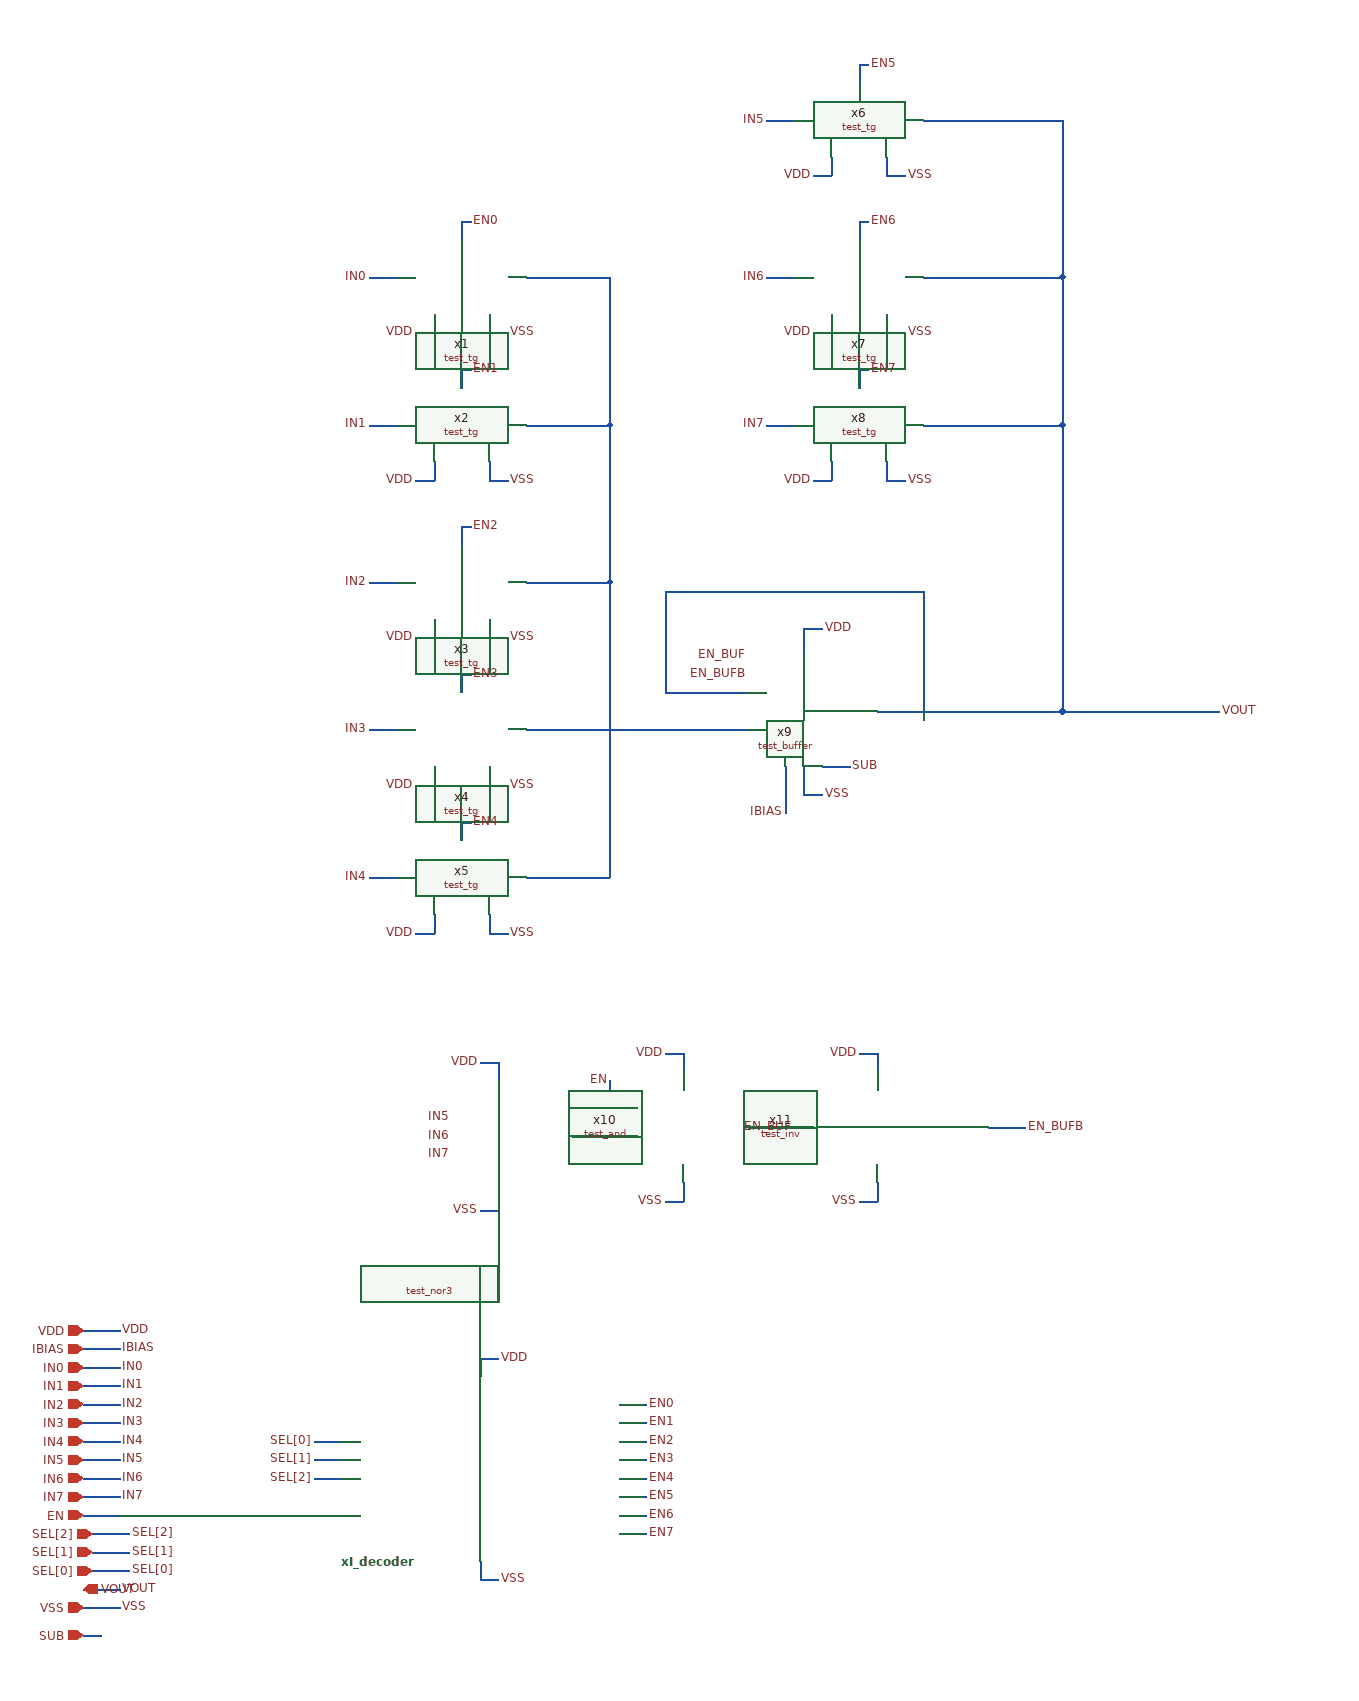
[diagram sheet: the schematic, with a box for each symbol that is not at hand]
v {xschem version=3.4.7 file_version=1.2}
G {}
K {}
V {}
S {}
E {}
N 150 -230 170 -230 {lab=SUB}
N 150 -520 190 -520 {lab=IN0}
N 150 -500 190 -500 {lab=IN1}
N 150 -480 190 -480 {lab=IN2}
N 150 -460 190 -460 {lab=IN3}
N 150 -440 190 -440 {lab=IN4}
N 150 -420 190 -420 {lab=IN5}
N 150 -400 190 -400 {lab=IN6}
N 150 -380 190 -380 {lab=IN7}
N 150 -360 190 -360 {lab=EN}
N 150 -540 190 -540 {lab=IBIAS}
N 150 -560 190 -560 {lab=VDD}
N 160 -340 200 -340 {lab=SEL[2]}
N 150 -280 190 -280 {lab=VOUT}
N 150 -260 190 -260 {lab=VSS}
N 460 -1700 490 -1700 {lab=IN0}
N 560 -1760 560 -1740 {lab=EN0}
N 560 -1760 570 -1760 {lab=EN0}
N 530 -1660 530 -1640 {lab=VDD}
N 510 -1640 530 -1640 {lab=VDD}
N 590 -1660 590 -1640 {lab=VSS}
N 590 -1640 610 -1640 {lab=VSS}
N 460 -1540 490 -1540 {lab=IN1}
N 560 -1600 560 -1580 {lab=EN1}
N 560 -1600 570 -1600 {lab=EN1}
N 530 -1500 530 -1480 {lab=VDD}
N 510 -1480 530 -1480 {lab=VDD}
N 590 -1500 590 -1480 {lab=VSS}
N 590 -1480 610 -1480 {lab=VSS}
N 460 -1370 490 -1370 {lab=IN2}
N 560 -1430 560 -1410 {lab=EN2}
N 560 -1430 570 -1430 {lab=EN2}
N 530 -1330 530 -1310 {lab=VDD}
N 510 -1310 530 -1310 {lab=VDD}
N 590 -1330 590 -1310 {lab=VSS}
N 590 -1310 610 -1310 {lab=VSS}
N 460 -1210 490 -1210 {lab=IN3}
N 560 -1270 560 -1250 {lab=EN3}
N 560 -1270 570 -1270 {lab=EN3}
N 530 -1170 530 -1150 {lab=VDD}
N 510 -1150 530 -1150 {lab=VDD}
N 590 -1170 590 -1150 {lab=VSS}
N 590 -1150 610 -1150 {lab=VSS}
N 460 -1050 490 -1050 {lab=IN4}
N 560 -1110 560 -1090 {lab=EN4}
N 560 -1110 570 -1110 {lab=EN4}
N 530 -1010 530 -990 {lab=VDD}
N 510 -990 530 -990 {lab=VDD}
N 590 -1010 590 -990 {lab=VSS}
N 590 -990 610 -990 {lab=VSS}
N 890 -1870 920 -1870 {lab=IN5}
N 990 -1930 990 -1910 {lab=EN5}
N 990 -1930 1000 -1930 {lab=EN5}
N 960 -1830 960 -1810 {lab=VDD}
N 940 -1810 960 -1810 {lab=VDD}
N 1020 -1830 1020 -1810 {lab=VSS}
N 1020 -1810 1040 -1810 {lab=VSS}
N 890 -1700 920 -1700 {lab=IN6}
N 990 -1760 990 -1740 {lab=EN6}
N 990 -1760 1000 -1760 {lab=EN6}
N 960 -1660 960 -1640 {lab=VDD}
N 940 -1640 960 -1640 {lab=VDD}
N 1020 -1660 1020 -1640 {lab=VSS}
N 1020 -1640 1040 -1640 {lab=VSS}
N 890 -1540 920 -1540 {lab=IN7}
N 990 -1600 990 -1580 {lab=EN7}
N 990 -1600 1000 -1600 {lab=EN7}
N 960 -1500 960 -1480 {lab=VDD}
N 940 -1480 960 -1480 {lab=VDD}
N 1020 -1500 1020 -1480 {lab=VSS}
N 1020 -1480 1040 -1480 {lab=VSS}
N 630 -1210 870 -1210 {lab=#net1}
N 630 -1370 720 -1370 {lab=#net1}
N 720 -1370 720 -1210 {lab=#net1}
N 630 -1540 720 -1540 {lab=#net1}
N 720 -1540 720 -1370 {lab=#net1}
N 630 -1700 720 -1700 {lab=#net1}
N 720 -1700 720 -1540 {lab=#net1}
N 630 -1050 720 -1050 {lab=#net1}
N 720 -1210 720 -1050 {lab=#net1}
N 1060 -1870 1210 -1870 {lab=VOUT}
N 1060 -1700 1200 -1700 {lab=VOUT}
N 1200 -1700 1210 -1700 {lab=VOUT}
N 1210 -1870 1210 -1700 {lab=VOUT}
N 1060 -1540 1210 -1540 {lab=VOUT}
N 1210 -1700 1210 -1540 {lab=VOUT}
N 930 -1320 930 -1290 {lab=VDD}
N 930 -1320 950 -1320 {lab=VDD}
N 930 -1170 930 -1140 {lab=VSS}
N 930 -1140 950 -1140 {lab=VSS}
N 1330 -1230 1380 -1230 {lab=VOUT}
N 160 -320 200 -320 {lab=SEL[1]}
N 160 -300 200 -300 {lab=SEL[0]}
N 580 -530 580 -510 {lab=VDD}
N 580 -530 600 -530 {lab=VDD}
N 580 -310 580 -290 {lab=VSS}
N 580 -290 600 -290 {lab=VSS}
N 400 -400 430 -400 {lab=SEL[2]}
N 400 -440 430 -440 {lab=SEL[0]}
N 400 -420 430 -420 {lab=SEL[1]}
N 730 -480 760 -480 {lab=EN0}
N 730 -460 760 -460 {lab=EN1}
N 730 -440 760 -440 {lab=EN2}
N 730 -420 760 -420 {lab=EN3}
N 730 -400 760 -400 {lab=EN4}
N 730 -380 760 -380 {lab=EN5}
N 730 -360 760 -360 {lab=EN6}
N 730 -340 760 -340 {lab=EN7}
N 600 -850 600 -830 {lab=VDD}
N 580 -850 600 -850 {lab=VDD}
N 600 -710 600 -690 {lab=VSS}
N 580 -690 600 -690 {lab=VSS}
N 800 -860 800 -840 {lab=VDD}
N 780 -860 800 -860 {lab=VDD}
N 800 -720 800 -700 {lab=VSS}
N 780 -700 800 -700 {lab=VSS}
N 680 -770 750 -770 {lab=#net2}
N 720 -800 750 -800 {lab=EN}
N 720 -830 720 -800 {lab=EN}
N 1210 -1540 1210 -1230 {lab=VOUT}
N 1010 -1230 1210 -1230 {lab=VOUT}
N 1210 -1230 1330 -1230 {lab=VOUT}
N 1010 -860 1010 -840 {lab=VDD}
N 990 -860 1010 -860 {lab=VDD}
N 1010 -720 1010 -700 {lab=VSS}
N 990 -700 1010 -700 {lab=VSS}
N 870 -780 940 -780 {lab=EN_BUF}
N 1130 -780 1170 -780 {lab=EN_BUFB}
N 780 -1250 870 -1250 {lab=VOUT}
N 780 -1360 780 -1250 {lab=VOUT}
N 780 -1360 1060 -1360 {lab=VOUT}
N 1060 -1360 1060 -1230 {lab=VOUT}
N 950 -1170 980 -1170 {lab=SUB}
N 910 -1170 910 -1120 {lab=#net3}
C {iopin.sym} 150 -560 2 0 {name=p1 lab=VDD}
C {iopin.sym} 150 -260 2 0 {name=p2 lab=VSS}
C {iopin.sym} 150 -230 2 0 {name=p3 lab=SUB}
C {noconn.sym} 170 -230 1 0 {name=l1}
C {iopin.sym} 150 -280 0 1 {name=p4 lab=VOUT}
C {iopin.sym} 150 -540 2 0 {name=p6 lab=IBIAS}
C {ipin.sym} 150 -360 0 0 {name=p5 lab=EN}
C {ipin.sym} 160 -340 0 0 {name=p7 lab=SEL[2]}
C {iopin.sym} 150 -520 2 0 {name=p8 lab=IN0}
C {iopin.sym} 150 -500 2 0 {name=p9 lab=IN1
}
C {iopin.sym} 150 -480 2 0 {name=p10 lab=IN2}
C {iopin.sym} 150 -460 2 0 {name=p11 lab=IN3}
C {iopin.sym} 150 -440 2 0 {name=p12 lab=IN4}
C {iopin.sym} 150 -420 2 0 {name=p13 lab=IN5}
C {iopin.sym} 150 -400 2 0 {name=p14 lab=IN6}
C {iopin.sym} 150 -380 2 0 {name=p15 lab=IN7}
C {libs/core_test/test_tg/test_tg.sym} 490 -1660 0 0 {name=x1}
C {lab_pin.sym} 190 -520 0 1 {name=p16 sig_type=std_logic lab=IN0}
C {lab_pin.sym} 190 -500 0 1 {name=p17 sig_type=std_logic lab=IN1}
C {lab_pin.sym} 190 -480 0 1 {name=p18 sig_type=std_logic lab=IN2}
C {lab_pin.sym} 190 -460 0 1 {name=p19 sig_type=std_logic lab=IN3}
C {lab_pin.sym} 190 -440 0 1 {name=p20 sig_type=std_logic lab=IN4}
C {lab_pin.sym} 190 -420 0 1 {name=p21 sig_type=std_logic lab=IN5}
C {lab_pin.sym} 190 -400 0 1 {name=p22 sig_type=std_logic lab=IN6}
C {lab_pin.sym} 190 -380 0 1 {name=p23 sig_type=std_logic lab=IN7}
C {lab_pin.sym} 190 -540 0 1 {name=p25 sig_type=std_logic lab=IBIAS}
C {lab_pin.sym} 190 -560 0 1 {name=p26 sig_type=std_logic lab=VDD}
C {lab_pin.sym} 200 -340 0 1 {name=p27 sig_type=std_logic lab=SEL[2]}
C {lab_pin.sym} 190 -280 0 1 {name=p28 sig_type=std_logic lab=VOUT}
C {lab_pin.sym} 190 -260 0 1 {name=p29 sig_type=std_logic lab=VSS}
C {lab_pin.sym} 460 -1700 0 0 {name=p30 sig_type=std_logic lab=IN0}
C {lab_pin.sym} 510 -1640 0 0 {name=p31 sig_type=std_logic lab=VDD}
C {lab_pin.sym} 610 -1640 0 1 {name=p32 sig_type=std_logic lab=VSS}
C {libs/core_test/test_tg/test_tg.sym} 490 -1500 0 0 {name=x2}
C {lab_pin.sym} 460 -1540 0 0 {name=p33 sig_type=std_logic lab=IN1}
C {lab_pin.sym} 510 -1480 0 0 {name=p34 sig_type=std_logic lab=VDD}
C {lab_pin.sym} 610 -1480 0 1 {name=p35 sig_type=std_logic lab=VSS}
C {libs/core_test/test_tg/test_tg.sym} 490 -1330 0 0 {name=x3}
C {lab_pin.sym} 460 -1370 0 0 {name=p36 sig_type=std_logic lab=IN2}
C {lab_pin.sym} 510 -1310 0 0 {name=p37 sig_type=std_logic lab=VDD}
C {lab_pin.sym} 610 -1310 0 1 {name=p38 sig_type=std_logic lab=VSS}
C {libs/core_test/test_tg/test_tg.sym} 490 -1170 0 0 {name=x4}
C {lab_pin.sym} 460 -1210 0 0 {name=p39 sig_type=std_logic lab=IN3}
C {lab_pin.sym} 510 -1150 0 0 {name=p40 sig_type=std_logic lab=VDD}
C {lab_pin.sym} 610 -1150 0 1 {name=p41 sig_type=std_logic lab=VSS}
C {libs/core_test/test_tg/test_tg.sym} 490 -1010 0 0 {name=x5}
C {lab_pin.sym} 460 -1050 0 0 {name=p42 sig_type=std_logic lab=IN4}
C {lab_pin.sym} 510 -990 0 0 {name=p43 sig_type=std_logic lab=VDD}
C {lab_pin.sym} 610 -990 0 1 {name=p44 sig_type=std_logic lab=VSS}
C {libs/core_test/test_tg/test_tg.sym} 920 -1830 0 0 {name=x6}
C {lab_pin.sym} 890 -1870 0 0 {name=p45 sig_type=std_logic lab=IN5}
C {lab_pin.sym} 940 -1810 0 0 {name=p46 sig_type=std_logic lab=VDD}
C {lab_pin.sym} 1040 -1810 0 1 {name=p47 sig_type=std_logic lab=VSS}
C {libs/core_test/test_tg/test_tg.sym} 920 -1660 0 0 {name=x7}
C {lab_pin.sym} 890 -1700 0 0 {name=p48 sig_type=std_logic lab=IN6}
C {lab_pin.sym} 940 -1640 0 0 {name=p49 sig_type=std_logic lab=VDD}
C {lab_pin.sym} 1040 -1640 0 1 {name=p50 sig_type=std_logic lab=VSS}
C {libs/core_test/test_tg/test_tg.sym} 920 -1500 0 0 {name=x8}
C {lab_pin.sym} 890 -1540 0 0 {name=p51 sig_type=std_logic lab=IN7}
C {lab_pin.sym} 940 -1480 0 0 {name=p52 sig_type=std_logic lab=VDD}
C {lab_pin.sym} 1040 -1480 0 1 {name=p53 sig_type=std_logic lab=VSS}
C {libs/core_test/test_buffer/test_buffer.sym} 870 -1170 0 0 {name=x9}
C {lab_pin.sym} 1000 -1600 0 1 {name=p54 sig_type=std_logic lab=EN7}
C {lab_pin.sym} 1000 -1760 0 1 {name=p55 sig_type=std_logic lab=EN6}
C {lab_pin.sym} 1000 -1930 0 1 {name=p56 sig_type=std_logic lab=EN5}
C {lab_pin.sym} 570 -1110 0 1 {name=p57 sig_type=std_logic lab=EN4}
C {lab_pin.sym} 570 -1270 0 1 {name=p58 sig_type=std_logic lab=EN3}
C {lab_pin.sym} 570 -1430 0 1 {name=p59 sig_type=std_logic lab=EN2}
C {lab_pin.sym} 570 -1600 0 1 {name=p60 sig_type=std_logic lab=EN1}
C {lab_pin.sym} 570 -1760 0 1 {name=p61 sig_type=std_logic lab=EN0}
C {lab_pin.sym} 950 -1320 0 1 {name=p62 sig_type=std_logic lab=VDD}
C {lab_pin.sym} 950 -1140 0 1 {name=p63 sig_type=std_logic lab=VSS}
C {lab_pin.sym} 1380 -1230 0 1 {name=p64 sig_type=std_logic lab=VOUT}
C {ipin.sym} 160 -320 0 0 {name=p24 lab=SEL[1]}
C {lab_pin.sym} 200 -320 0 1 {name=p65 sig_type=std_logic lab=SEL[1]}
C {ipin.sym} 160 -300 0 0 {name=p66 lab=SEL[0]}
C {lab_pin.sym} 200 -300 0 1 {name=p67 sig_type=std_logic lab=SEL[0]}
C {libs/core_test/test_decoder/test_decoder.sym} 430 -310 0 0 {name=xI_decoder}
C {lab_pin.sym} 600 -530 0 1 {name=p68 sig_type=std_logic lab=VDD}
C {lab_pin.sym} 600 -290 0 1 {name=p69 sig_type=std_logic lab=VSS}
C {lab_pin.sym} 400 -400 0 0 {name=p70 sig_type=std_logic lab=SEL[2]}
C {lab_pin.sym} 400 -420 0 0 {name=p71 sig_type=std_logic lab=SEL[1]}
C {lab_pin.sym} 400 -440 0 0 {name=p72 sig_type=std_logic lab=SEL[0]}
C {lab_pin.sym} 760 -480 0 1 {name=p73 sig_type=std_logic lab=EN0}
C {lab_pin.sym} 760 -460 0 1 {name=p74 sig_type=std_logic lab=EN1}
C {lab_pin.sym} 760 -440 0 1 {name=p75 sig_type=std_logic lab=EN2}
C {lab_pin.sym} 760 -420 0 1 {name=p76 sig_type=std_logic lab=EN3}
C {lab_pin.sym} 760 -400 0 1 {name=p77 sig_type=std_logic lab=EN4}
C {lab_pin.sym} 760 -380 0 1 {name=p78 sig_type=std_logic lab=EN5}
C {lab_pin.sym} 760 -360 0 1 {name=p79 sig_type=std_logic lab=EN6}
C {lab_pin.sym} 760 -340 0 1 {name=p80 sig_type=std_logic lab=EN7}
C {libs/core_test/test_and/test_and.sym} 750 -720 0 0 {name=x10}
C {libs/core_test/test_nor3/test_nor3.sym} 550 -710 0 0 {}
C {lab_pin.sym} 550 -790 0 0 {name=p81 sig_type=std_logic lab=IN5}
C {lab_pin.sym} 550 -770 0 0 {name=p82 sig_type=std_logic lab=IN6}
C {lab_pin.sym} 550 -750 0 0 {name=p83 sig_type=std_logic lab=IN7}
C {lab_pin.sym} 580 -850 0 0 {name=p84 sig_type=std_logic lab=VDD}
C {lab_pin.sym} 580 -690 0 0 {name=p85 sig_type=std_logic lab=VSS}
C {lab_pin.sym} 780 -860 0 0 {name=p86 sig_type=std_logic lab=VDD}
C {lab_pin.sym} 780 -700 0 0 {name=p87 sig_type=std_logic lab=VSS}
C {lab_pin.sym} 720 -830 0 0 {name=p88 sig_type=std_logic lab=EN}
C {libs/core_test/test_inv/test_inv.sym} 940 -720 0 0 {name=x11}
C {lab_pin.sym} 990 -860 0 0 {name=p89 sig_type=std_logic lab=VDD}
C {lab_pin.sym} 990 -700 0 0 {name=p90 sig_type=std_logic lab=VSS}
C {lab_wire.sym} 920 -780 0 0 {name=p91 sig_type=std_logic lab=EN_BUF}
C {lab_wire.sym} 1170 -780 0 1 {name=p92 sig_type=std_logic lab=EN_BUFB}
C {lab_wire.sym} 870 -1270 0 0 {name=p93 sig_type=std_logic lab=EN_BUFB}
C {lab_wire.sym} 870 -1290 0 0 {name=p94 sig_type=std_logic lab=EN_BUF}
C {lab_pin.sym} 980 -1170 0 1 {name=p95 sig_type=std_logic lab=SUB}
C {lab_wire.sym} 910 -1120 3 0 {name=p96 sig_type=std_logic lab=IBIAS}
